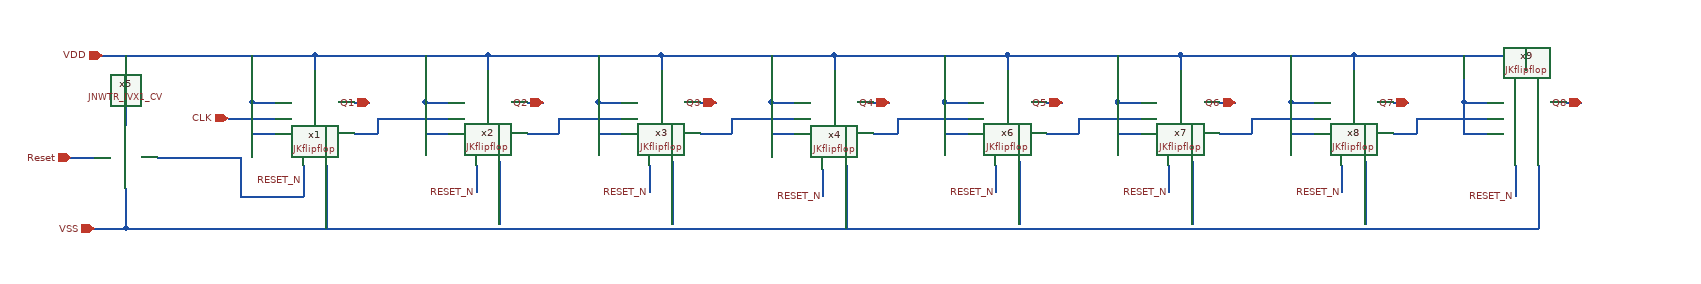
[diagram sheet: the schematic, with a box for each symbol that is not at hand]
v {xschem version=3.4.6 file_version=1.2}
G {}
K {}
V {}
S {}
E {}
N 70 -160 70 -140 {lab=VDD}
N 20 -160 70 -160 {lab=VDD}
N 70 -160 290 -160 {lab=VDD}
N 290 -160 290 -140 {lab=VDD}
N 290 -160 510 -160 {lab=VDD}
N 510 -160 510 -140 {lab=VDD}
N 510 -160 730 -160 {lab=VDD}
N 730 -160 730 -140 {lab=VDD}
N 70 60 290 60 {lab=VSS}
N 290 60 510 60 {lab=VSS}
N 510 60 730 60 {lab=VSS}
N -20 60 70 60 {lab=VSS}
N -10 -100 20 -100 {lab=VDD}
N -40 -160 20 -160 {lab=VDD}
N 210 -160 210 -100 {lab=VDD}
N 210 -100 240 -100 {lab=VDD}
N 430 -100 460 -100 {lab=VDD}
N 650 -100 680 -100 {lab=VDD}
N -40 60 -20 60 {lab=VSS}
N -40 -80 20 -80 {lab=CLK}
N -130 -30 -100 -30 {lab=RESET_N}
N -200 -160 -40 -160 {lab=VDD}
N -240 -30 -210 -30 {lab=Reset}
N -170 -160 -170 -70 {lab=VDD}
N -170 10 -170 60 {lab=VSS}
N -210 60 -170 60 {lab=VSS}
N -170 60 -40 60 {lab=VSS}
N -10 -160 -10 -100 {lab=VDD}
N -10 -60 20 -60 {lab=VDD}
N 430 -160 430 -100 {lab=VDD}
N 650 -160 650 -100 {lab=VDD}
N 120 -60 150 -60 {lab=#net1}
N 150 -80 150 -60 {lab=#net1}
N 150 -80 240 -80 {lab=#net1}
N 380 -80 460 -80 {lab=#net2}
N 380 -80 380 -60 {lab=#net2}
N 340 -60 380 -60 {lab=#net2}
N 600 -80 680 -80 {lab=#net3}
N 560 -60 600 -60 {lab=#net3}
N 600 -80 600 -60 {lab=#net3}
N 730 -160 950 -160 {lab=VDD}
N 950 -160 950 -140 {lab=VDD}
N 950 -160 1170 -160 {lab=VDD}
N 1170 -160 1170 -140 {lab=VDD}
N 1170 -160 1390 -160 {lab=VDD}
N 1390 -160 1390 -140 {lab=VDD}
N 730 60 950 60 {lab=VSS}
N 950 60 1170 60 {lab=VSS}
N 1170 60 1390 60 {lab=VSS}
N 870 -160 870 -100 {lab=VDD}
N 870 -100 900 -100 {lab=VDD}
N 1090 -100 1120 -100 {lab=VDD}
N 1310 -100 1340 -100 {lab=VDD}
N 1090 -160 1090 -100 {lab=VDD}
N 1310 -160 1310 -100 {lab=VDD}
N 810 -80 900 -80 {lab=#net4}
N 1040 -80 1120 -80 {lab=#net5}
N 1040 -80 1040 -60 {lab=#net5}
N 1000 -60 1040 -60 {lab=#net5}
N 1260 -80 1340 -80 {lab=#net6}
N 1220 -60 1260 -60 {lab=#net6}
N 1260 -80 1260 -60 {lab=#net6}
N 1390 -160 1610 -160 {lab=VDD}
N 1610 -160 1610 -140 {lab=VDD}
N 1390 60 1610 60 {lab=VSS}
N 1530 -160 1530 -100 {lab=VDD}
N 1530 -100 1560 -100 {lab=VDD}
N 1470 -80 1560 -80 {lab=#net7}
N 1440 -60 1470 -60 {lab=#net7}
N 1470 -70 1470 -60 {lab=#net7}
N 1470 -80 1470 -70 {lab=#net7}
N 780 -60 810 -60 {lab=#net4}
N 810 -80 810 -60 {lab=#net4}
N 120 -100 140 -100 {lab=Q1}
N 340 -100 360 -100 {lab=Q2}
N 430 -60 460 -60 {lab=VDD}
N 560 -100 580 -100 {lab=Q3}
N 650 -60 680 -60 {lab=VDD}
N 1660 -100 1680 -100 {lab=Q8}
N 1440 -100 1460 -100 {lab=Q7}
N 1530 -60 1560 -60 {lab=VDD}
N 1220 -100 1240 -100 {lab=Q6}
N 1310 -60 1340 -60 {lab=VDD}
N 1000 -100 1020 -100 {lab=Q5}
N 1090 -60 1120 -60 {lab=VDD}
N 780 -100 800 -100 {lab=Q4}
N 870 -60 900 -60 {lab=VDD}
N -100 -30 -90 -30 {lab=RESET_N}
N 85 -20 85 60 {lab=VSS}
N -90 -30 -25 -30 {lab=RESET_N}
N -25 -30 -25 -20 {lab=RESET_N}
N 55 -20 55 -0 {lab=RESET_N}
N -25 -20 -25 -0 {lab=RESET_N}
N -10 -100 -10 -60 {lab=VDD}
N 55 0 55 20 {lab=RESET_N}
N -25 20 55 20 {lab=RESET_N}
N -25 0 -25 20 {lab=RESET_N}
N 1625 -20 1625 60 {lab=VSS}
N 1610 60 1625 60 {lab=VSS}
N 1595 -15 1595 20 {lab=RESET_N}
N 1595 -20 1595 -15 {lab=RESET_N}
N 745 -20 745 60 {lab=VSS}
N 715 -15 715 20 {lab=RESET_N}
N 965 -25 965 55 {lab=#net8}
N 935 -20 935 15 {lab=RESET_N}
N 1185 -25 1185 55 {lab=#net9}
N 1155 -20 1155 15 {lab=RESET_N}
N 1405 -25 1405 55 {lab=#net10}
N 1375 -20 1375 15 {lab=RESET_N}
N 305 -25 305 55 {lab=#net11}
N 275 -20 275 15 {lab=RESET_N}
N 525 -25 525 55 {lab=#net12}
N 495 -20 495 15 {lab=RESET_N}
N 430 -100 430 -60 {lab=VDD}
N 210 -60 240 -60 {lab=VDD}
N 210 -100 210 -60 {lab=VDD}
N 1310 -100 1310 -60 {lab=VDD}
N 1530 -100 1530 -60 {lab=VDD}
N 650 -100 650 -60 {lab=VDD}
N 870 -100 870 -60 {lab=VDD}
N 1090 -100 1090 -60 {lab=VDD}
C {JNW_GR05_SKY130A/JKflipflop.sym} 70 -80 0 0 {name=x1}
C {JNW_GR05_SKY130A/JKflipflop.sym} 290 -80 0 0 {name=x2}
C {JNW_GR05_SKY130A/JKflipflop.sym} 510 -80 0 0 {name=x3}
C {JNW_GR05_SKY130A/JKflipflop.sym} 730 -80 0 0 {name=x4}
C {devices/ipin.sym} -200 -160 0 0 {name=p4 lab=VDD}
C {devices/opin.sym} 140 -100 2 1 {name=p19 lab=Q1
}
C {devices/ipin.sym} -210 60 0 0 {name=p1 lab=VSS}
C {devices/ipin.sym} -40 -80 0 0 {name=p2 lab=CLK}
C {devices/opin.sym} 360 -100 2 1 {name=p3 lab=Q2
}
C {devices/opin.sym} 580 -100 2 1 {name=p5 lab=Q3
}
C {devices/opin.sym} 800 -100 2 1 {name=p6 lab=Q4}
C {devices/ipin.sym} -240 -30 0 0 {name=p8 lab=Reset
}
C {JNW_TR_SKY130A/JNWTR_IVX1_CV.sym} -210 -30 0 0 {name=x5 }
C {devices/lab_pin.sym} 55 0 0 0 {name=p7 sig_type=std_logic lab=RESET_N
}
C {JNW_GR05_SKY130A/JKflipflop.sym} 950 -80 0 0 {name=x6}
C {JNW_GR05_SKY130A/JKflipflop.sym} 1170 -80 0 0 {name=x7}
C {JNW_GR05_SKY130A/JKflipflop.sym} 1390 -80 0 0 {name=x8}
C {devices/opin.sym} 1020 -100 2 1 {name=p9 lab=Q5
}
C {devices/opin.sym} 1240 -100 2 1 {name=p13 lab=Q6

}
C {devices/opin.sym} 1460 -100 2 1 {name=p14 lab=Q7}
C {JNW_GR05_SKY130A/JKflipflop.sym} 1610 -80 0 0 {name=x9}
C {devices/opin.sym} 1680 -100 2 1 {name=p18 lab=Q8
}
C {devices/lab_pin.sym} 1595 20 0 0 {name=p10 sig_type=std_logic lab=RESET_N
}
C {devices/lab_pin.sym} 715 20 0 0 {name=p21 sig_type=std_logic lab=RESET_N
}
C {devices/lab_pin.sym} 935 15 0 0 {name=p22 sig_type=std_logic lab=RESET_N
}
C {devices/lab_pin.sym} 1155 15 0 0 {name=p23 sig_type=std_logic lab=RESET_N
}
C {devices/lab_pin.sym} 1375 15 0 0 {name=p24 sig_type=std_logic lab=RESET_N
}
C {devices/lab_pin.sym} 275 15 0 0 {name=p25 sig_type=std_logic lab=RESET_N
}
C {devices/lab_pin.sym} 495 15 0 0 {name=p26 sig_type=std_logic lab=RESET_N
}
